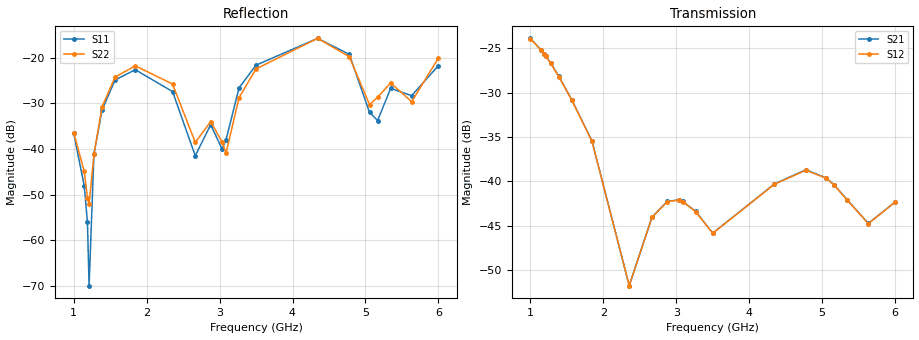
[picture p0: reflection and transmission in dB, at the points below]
!Agilent Technologies,E8364B,MY43040528,A.07.50.67
!Agilent E8364B: A.07.50.67
!Date: Sunday, March 01, 2026 22:44:19
!Correction: S11(Full 2 Port(1,2))
!S21(Full 2 Port(1,2))
!S12(Full 2 Port(1,2))
!S22(Full 2 Port(1,2))
!S2P File: Measurements: S11, S21, S12, S22:
# Hz S  dB  R 50
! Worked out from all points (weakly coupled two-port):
!   451 points, 1 GHz to 6 GHz, reference 50 ohm
!   highest |S21| = -23.86 dB at 1 GHz (marker M1); lowest = -51.8 dB at 2.356 GHz (marker M2)
!   lowest |S11| = -69.9 dB at 1.211 GHz (marker M3), VSWR 1.00, Z = 50 - j0.0208 ohm
!   |S11| at or under -10 dB: start of sweep to end of sweep
!   |S22| runs from -52.1 to -15.7 dB; largest |S21 - S12| = 0.00026
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1e9  -36.54 15.7  -23.86 154.8  -23.90 154.9  -36.43 -28.3
1.144444e9  -48.04 14.5  -25.14 72.4  -25.18 72.5  -44.91 -10.5
1.188889e9  -56.09 13.0  -25.61 47.2  -25.63 47.2  -50.65 30.1
1.211111e9  -69.95 -139.2  -25.85 34.6  -25.88 34.6  -52.11 78.2
1.277778e9  -41.14 -161.2  -26.63 -3.1  -26.67 -3.0  -41.19 127.5
1.388889e9  -31.47 176.7  -28.14 -64.9  -28.17 -64.9  -30.77 105.7
1.566667e9  -24.90 134.0  -30.78 -161.0  -30.81 -161.1  -24.26 58.8
1.844444e9  -22.64 76.6  -35.45 51.5  -35.48 51.5  -21.78 -10.8
2.355556e9  -27.43 -0.3  -51.79 -149.0  -51.78 -148.7  -25.78 -115.2
2.666667e9  -41.48 40.5  -44.07 103.8  -44.08 104.1  -38.57 -123.2
2.877778e9  -34.69 46.0  -42.26 -4.8  -42.29 -4.9  -34.00 -111.9
3.033333e9  -39.97 63.4  -42.11 -86.4  -42.13 -86.4  -38.46 -124.7
3.088889e9  -37.96 103.1  -42.26 -115.5  -42.29 -115.4  -40.88 -95.5
3.266667e9  -26.63 102.0  -43.40 153.8  -43.44 153.8  -28.77 -71.0
3.5e9  -21.64 63.6  -45.86 46.4  -45.88 46.6  -22.45 -120.5
4.344444e9  -15.77 -41.6  -40.30 24.2  -40.34 24.2  -15.77 100.0
4.777778e9  -19.26 -115.8  -38.70 143.1  -38.75 143.2  -19.78 13.5
5.055556e9  -32.00 -144.6  -39.62 -20.0  -39.66 -20.0  -30.28 3.3
5.166667e9  -33.77 -72.7  -40.42 -86.9  -40.45 -87.0  -28.68 28.1
5.344444e9  -26.73 -76.4  -42.10 162.2  -42.13 162.1  -25.53 10.1
5.633333e9  -28.32 -85.5  -44.76 -37.8  -44.79 -37.9  -29.64 4.3
6e9  -21.73 -82.1  -42.32 60.3  -42.36 60.3  -20.07 -19.3
